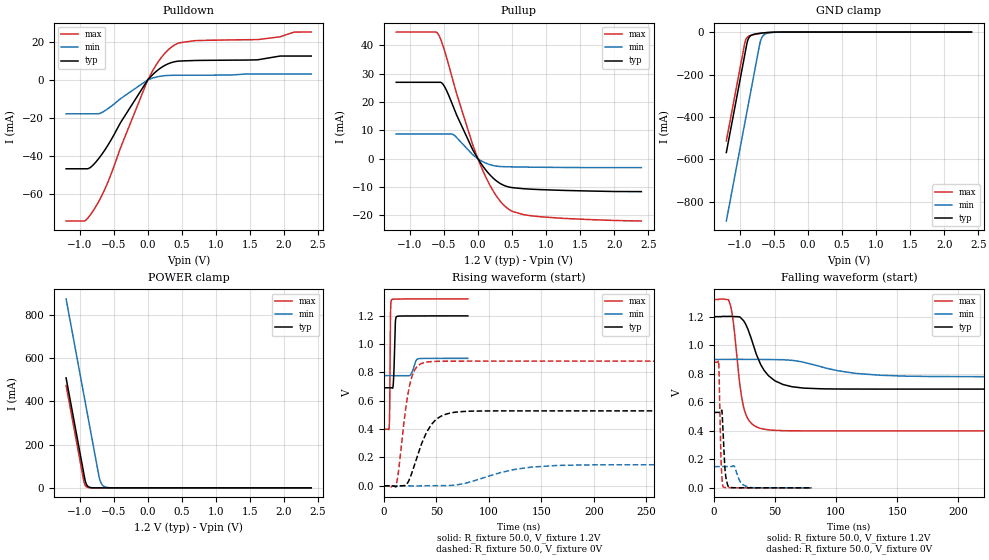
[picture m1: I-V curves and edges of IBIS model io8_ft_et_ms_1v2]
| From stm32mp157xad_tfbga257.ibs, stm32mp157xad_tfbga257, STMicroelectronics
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[Model]   io8_ft_et_ms_1v2
Model_type I/O
Polarity   Non-Inverting
Enable   Active-Low
| CAP_THRESHOLD on pad IOFT is "UDTCAPC" :
| Rising=20.00f vddiom   Falling=80.00f vddiom
| C_comp min and max val. don't necessarily correlate with the min and max pvt
| but are the smallest and greatest pad capacitance found.
| var   typ   min   max
C_comp   3.10945pF  3.08865pF  3.12940pF
|C_comp_pullup   1.82110pF  1.58845pF  1.75300pF
|C_comp_pulldown   1.28835pF  1.50020pF  1.37640pF
Vinl = 360.0mV
Vinh = 792.0mV
Vmeas = 600.0mV   | Reference voltage for timing measurements
Cref  = 50.0pF   | Timing specification test load capacitance value
Rref  = 100.0MOhm   | Timing specification test load resistance value
Vref  = 0V   | Timing specification test load voltage
[Model Spec]
| TIME_THRESHOLD on pin ZIV11 is "CMOS" :
| Rising=40.00f vdd   Falling=60.00f vdd
Vinl 463.60000mV 362.60000mV 506.60000mV
Vinh 741.40000mV 545.40000mV 817.40000mV
| variable   typ   min   max
[Temperature Range] 25.0 140.0 -40.0
| variable   typ   min   max
[Voltage Range] 1.2V 900.0mV 1.32V
| variable   typ   min   max
[POWER Clamp Reference] 1.2V 900.0mV 1.32V
| variable   typ   min   max
[GND Clamp Reference] 0V 0V 0V
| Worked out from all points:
|   slope of the pulldown table from 0 to 0.18 V, typ, clamps not added: 30 ohm
|   slope of the pullup table from 0 to 0.18 V, typ, clamps not added: 31.1 ohm
|   GND clamp passes 1 mA (typ) near -0.52 V on its own axis
|   POWER clamp passes 1 mA (typ) near -0.83 V on its own axis
|   rising waveform, R_fixture 50.0, V_fixture 1.2V: 20-80 % time 1.12ns typ, 3.33ns min, 572ps max; typ from 0.692 V to 1.2 V
|   falling waveform, R_fixture 50.0, V_fixture 1.2V: 20-80 % time 15.5ns typ, 40.7ns min, 7.6ns max; typ from 1.2 V to 0.692 V
|   rising waveform, R_fixture 50.0, V_fixture 0V: 20-80 % time 17.1ns typ, 44.6ns min, 9.23ns max; typ from 0 V to 0.529 V
|   falling waveform, R_fixture 50.0, V_fixture 0V: 20-80 % time 2.03ns typ, 4.67ns min, 1.44ns max; typ from 0.529 V to 0 V
[POWER Clamp]
-1.2V     508.8mA    874.1mA    473.5mA
-940mV    66.83mA    432.1mA    31.5mA
-930mV    49.83mA    415.1mA    19.15mA
-910mV    22.88mA    381.1mA    7.077mA
-880mV    7.117mA    330.1mA    1.59mA
-830mV    1.017mA    245.1mA    132uA
-720mV    14.05uA    58.12mA    554nA
-690mV    4.373uA    25.03mA    124.8nA
-650mV    922.5nA    8.136mA    17.23nA
-600mV    132.6nA    1.998mA    1.565nA
-490mV    2.858nA    90.92uA    111.8pA
2.4V      0A         0A         0A
[GND Clamp]
-1.2V     -567.2mA   -889.7mA   -512.2mA
-930mV    -108.2mA   -430.7mA   -53.23mA
-920mV    -91.21mA   -413.7mA   -40.49mA
-890mV    -43.51mA   -362.7mA   -23.59mA
-860mV    -22.57mA   -311.7mA   -17.89mA
-810mV    -12.11mA   -226.7mA   -13.23mA
-710mV    -6.053mA   -57.05mA   -7.064mA
-680mV    -4.908mA   -27.37mA   -5.632mA
-640mV    -3.605mA   -11.51mA   -3.985mA
-560mV    -1.665mA   -3.218mA   -1.61mA
-360mV    -34.72uA   -209.4uA   -9.248uA
2.4V      3.415nA    1.206uA    162.7pA
| variable   typ   min   max
[Pullup Reference] 1.2V 900.0mV 1.32V
| variable   typ   min   max
[Pulldown Reference] 0V 0V 0V
[Pullup]
-1.2V     26.92mA    8.713mA    44.63mA
-620mV    26.92mA    8.713mA    44.63mA
-580mV    26.92mA    8.713mA    43.74mA
-500mV    25.78mA    8.713mA    38.84mA
-360mV    18.23mA    8.473mA    26.98mA
-80mV     3.323mA    1.49mA     5.159mA
10mV      -383.6uA   -162.4uA   -606.4uA
220mV     -6.756mA   -2.388mA   -11.2mA
430mV     -9.815mA   -2.848mA   -17.42mA
670mV     -10.58mA   -2.95mA    -19.72mA
900mV     -10.88mA   -3.014mA   -20.42mA
2.4V      -11.6mA    -3.141mA   -21.96mA
[Pulldown]
-1.2V     -46.7mA    -17.86mA   -74.13mA
-930mV    -46.7mA    -17.86mA   -74.13mA
-770mV    -43.45mA   -17.86mA   -66.94mA
-580mV    -33.98mA   -14.99mA   -53.18mA
0V        0A         -7pA       0A
170mV     5.742mA    1.791mA    10.3mA
340mV     8.972mA    2.348mA    16.97mA
460mV     9.857mA    2.399mA    19.42mA
690mV     10.15mA    2.431mA    20.56mA
1.61V     10.49mA    3.05mA     21.11mA
2.16V     12.49mA    3.05mA     25.09mA
2.4V      12.49mA    3.05mA     25.09mA
[Ramp]
dV/dt_r 317.41827mV/17.10377ns 89.23301mV/44.63158ns 528.12888mV/9.23167ns
dV/dt_f 304.67945mV/15.47689ns 73.17214mV/40.67867ns 552.41113mV/7.59992ns
R_load = 50.0
| Removed startup time: 0s 0s 0s  .
| Removed end time: 79.9ns.
[Rising Waveform]
R_fixture   = 50.0
V_fixture   = 1.2V
V_fixture_min = 900.0mV
V_fixture_max = 1.32V
0s        692.2mV    778mV      399.3mV
5ns       692.2mV    778mV      414.8mV
5.5ns     692.2mV    778mV      557.6mV
6.3ns     692.3mV    778mV      1.238V
7.2ns     691.8mV    778mV      1.312V
8.9ns     720.8mV    778mV      1.318V
10.8ns    1.15V      778mV      1.318V
12ns      1.194V     778mV      1.319V
32.5ns    1.2V       896.6mV    1.32V
79.9ns    1.2V       899.8mV    1.32V
| Removed startup time: 0s 0s 0s  .
| Removed end time: 799.9ns.
[Falling Waveform]
R_fixture   = 50.0
V_fixture   = 1.2V
V_fixture_min = 900.0mV
V_fixture_max = 1.32V
0s        1.2V       900mV      1.32V
13.6ns    1.202V     900mV      1.274V
16.3ns    1.2V       900.3mV    1.123V
22.3ns    1.189V     900.6mV    648.3mV
26.5ns    1.136V     900.4mV    505mV
37.9ns    868.2mV    900.3mV    417.1mV
45.8ns    777.6mV    900mV      405.2mV
73.6ns    699mV      879.6mV    399.4mV
156.9ns   692.2mV    783.1mV    399.3mV
799.9ns   692.2mV    778mV      399.3mV
| Removed startup time: 0s 0s 0s  .
| Removed end time: 799.9ns.
[Rising Waveform]
R_fixture   = 50.0
V_fixture   = 0V
V_fixture_min = 0V
V_fixture_max = 0V
0s        720.8nV    1.004uV    -324.7nV
11.9ns    -4.079mV   1.104uV    14.48mV
20.8ns    4.614mV    24.65uV    550.1mV
25.3ns    64.55mV    -656.4uV   736.8mV
31.4ns    200.8mV    -1.891mV   840.2mV
40.9ns    381.3mV    -67.88uV   873.7mV
56.3ns    498.1mV    637.2uV    879.6mV
83ns      527mV      28.84mV    880.1mV
165.5ns   528.9mV    143.6mV    880.2mV
799.9ns   529mV      148.7mV    880.2mV
| Removed startup time: 0s 0s 0s  .
| Removed end time: 79.9ns.
[Falling Waveform]
R_fixture   = 50.0
V_fixture   = 0V
V_fixture_min = 0V
V_fixture_max = 0V
0s        529mV      148.8mV    880.2mV
3.8ns     529mV      148.8mV    882.5mV
5.7ns     531.6mV    148.8mV    192mV
6.5ns     532.8mV    148.8mV    67.23mV
7.5ns     363mV      148.8mV    6.791mV
9.3ns     98.32mV    148.8mV    2.112mV
12.1ns    3.711mV    148.8mV    1.417mV
16.5ns    769.9uV    152mV      777uV
28.4ns    463.3uV    4.727mV    116.4uV
79.9ns    2.53uV     133.1uV    -1.894uV
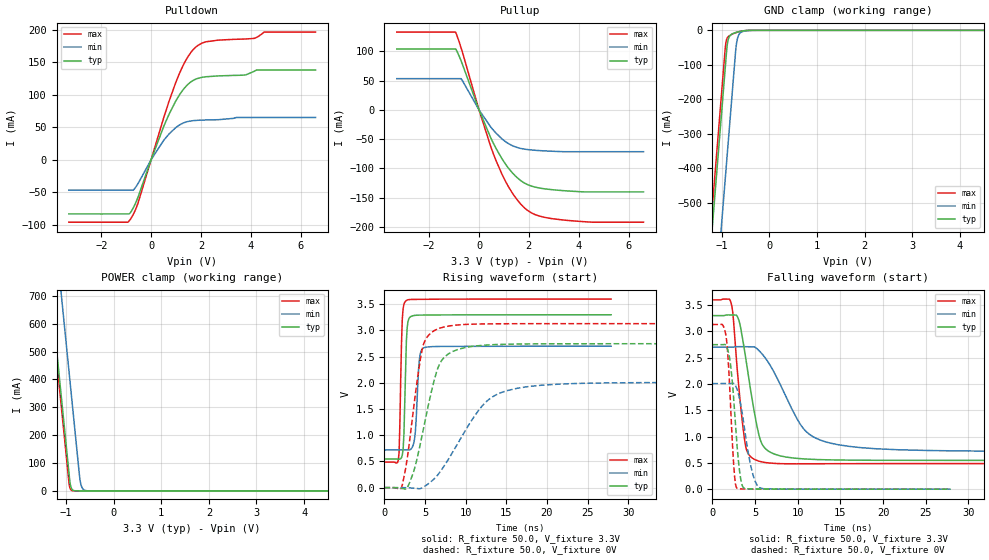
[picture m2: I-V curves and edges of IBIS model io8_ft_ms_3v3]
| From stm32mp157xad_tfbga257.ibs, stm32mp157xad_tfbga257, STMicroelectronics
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[Model]   io8_ft_ms_3v3
Model_type I/O
Polarity   Non-Inverting
Enable   Active-Low
| CAP_THRESHOLD on pad IOFT is "UDTCAPC" :
| Rising=20.00f vddiom   Falling=80.00f vddiom
| C_comp min and max val. don't necessarily correlate with the min and max pvt
| but are the smallest and greatest pad capacitance found.
| var   typ   min   max
C_comp   3.69202pF  3.65664pF  3.71215pF
|C_comp_pullup   2.23630pF  2.30075pF  2.13670pF
|C_comp_pulldown   1.45572pF  1.35589pF  1.57545pF
Vinl = 1.08V
Vinh = 2.16V
Vmeas = 1.65V   | Reference voltage for timing measurements
Cref  = 50.0pF   | Timing specification test load capacitance value
Rref  = 100.0MOhm   | Timing specification test load resistance value
Vref  = 0V   | Timing specification test load voltage
[Model Spec]
| TIME_THRESHOLD on pin ZIV11 is "CMOS" :
| Rising=40.00f vdd   Falling=60.00f vdd
Vinl 1.36060V 1.12960V 1.47360V
Vinh 1.71540V 1.45040V 1.82940V
| variable   typ   min   max
[Temperature Range] 25.0 140.0 -40.0
| variable   typ   min   max
[Voltage Range] 3.3V 2.7V 3.6V
| variable   typ   min   max
[POWER Clamp Reference] 3.3V 2.7V 3.6V
| variable   typ   min   max
[GND Clamp Reference] 0V 0V 0V
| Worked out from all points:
|   slope of the pulldown table from 0 to 0.495 V, typ, clamps not added: 9.86 ohm
|   slope of the pullup table from 0 to 0.495 V, typ, clamps not added: 9.93 ohm
|   GND clamp passes 1 mA (typ) near -0.52 V on its own axis
|   POWER clamp passes 1 mA (typ) near -0.83 V on its own axis
|   rising waveform, R_fixture 50.0, V_fixture 3.3V: 20-80 % time 280ps typ, 398ps min, 267ps max; typ from 0.547 V to 3.3 V
|   falling waveform, R_fixture 50.0, V_fixture 3.3V: 20-80 % time 1.7ns typ, 3.92ns min, 1.05ns max; typ from 3.3 V to 0.547 V
|   rising waveform, R_fixture 50.0, V_fixture 0V: 20-80 % time 2.38ns typ, 5.01ns min, 1.61ns max; typ from 0 V to 2.75 V
|   falling waveform, R_fixture 50.0, V_fixture 0V: 20-80 % time 808ps typ, 1.24ns min, 608ps max; typ from 2.75 V to 0 V
[POWER Clamp]
-3.3V     4.079A     4.444A     4.043A
-1.46V    950.8mA    1.316A     915.5mA
-1.28V    644.8mA    1.01A      609.5mA
-1.1V     338.8mA    704.1mA    303.5mA
-1.09V    321.8mA    687.1mA    286.5mA
-940mV    66.83mA    432.1mA    31.5mA
-910mV    22.88mA    381.1mA    7.077mA
-880mV    7.117mA    330.1mA    1.59mA
-710mV    9.523uA    43.89mA    337nA
-670mV    2.009uA    14.27mA    46.35nA
-590mV    90.76nA    1.508mA    1.088nA
6.6V      0A         0A         0A
[GND Clamp]
-3.3V     -4.139A    -4.461A    -4.081A
-1.26V    -670.8mA   -992.8mA   -613.3mA
-1.1V     -398.8mA   -720.8mA   -341.3mA
-930mV    -109.8mA   -431.8mA   -52.32mA
-890mV    -44.91mA   -363.8mA   -23.04mA
-870mV    -28.43mA   -329.8mA   -18.86mA
-760mV    -8.879mA   -142.8mA   -9.749mA
-710mV    -6.383mA   -58.04mA   -7.036mA
-670mV    -4.798mA   -22.41mA   -5.193mA
-610mV    -2.902mA   -7.057mA   -2.962mA
-500mV    -778.4uA   -1.643mA   -611.3uA
6.6V      9.179nA    3.066uA    465pA
| variable   typ   min   max
[Pullup Reference] 3.3V 2.7V 3.6V
| variable   typ   min   max
[Pulldown Reference] 0V 0V 0V
[Pullup]
-3.3V     103.9mA    53.38mA    132.9mA
-940mV    103.9mA    53.38mA    132.9mA
-720mV    83.88mA    53.38mA    106mA
0V        11.24pA    1.438nA    7.78pA
470mV     -47.62mA   -29.16mA   -62.69mA
690mV     -66.37mA   -40.04mA   -87.36mA
1.03V     -90.57mA   -53.18mA   -119.3mA
1.34V     -107.6mA   -61.16mA   -142.2mA
1.95V     -127.7mA   -67.75mA   -171.7mA
2.43V     -133.5mA   -69.51mA   -181.5mA
3.39V     -138mA     -71.4mA    -188.1mA
6.6V      -140.1mA   -71.44mA   -191.8mA
[Pulldown]
-3.3V     -83.56mA   -46.9mA    -96.31mA
-850mV    -82.46mA   -46.9mA    -92.78mA
-710mV    -73.83mA   -46.68mA   -83.86mA
-520mV    -57.22mA   -36.51mA   -66.23mA
0V        30fA       0A         200fA
720mV     70.07mA    39.69mA    90.11mA
1.29V     108.2mA    56.55mA    145.7mA
1.84V     125mA      60.7mA     175.1mA
2.21V     127.9mA    61.3mA     181.9mA
4.13V     136.2mA    65.14mA    187.1mA
4.54V     138.3mA    65.14mA    196.8mA
6.6V      138.3mA    65.14mA    196.8mA
[Ramp]
dV/dt_r 1.64845V/2.38267ns 1.20455V/5.00825ns 1.87844V/1.60905ns
dV/dt_f 1.65161V/1.69953ns 1.18897V/3.915ns 1.86819V/1.05154ns
R_load = 50.0
| Removed startup time: 0s 0s 0s  .
| Removed end time: 27.9ns.
[Rising Waveform]
R_fixture   = 50.0
V_fixture   = 3.3V
V_fixture_min = 2.7V
V_fixture_max = 3.6V
0s        547.3mV    718.4mV    486.3mV
1.7ns     545.4mV    718.4mV    521.9mV
1.8ns     543.4mV    718.4mV    669.2mV
2.2ns     624.6mV    718.4mV    3.229V
2.4ns     1.033V     718.5mV    3.503V
2.7ns     2.8V       717.9mV    3.573V
3.7ns     3.288V     925.2mV    3.594V
4.3ns     3.294V     2.444V     3.596V
4.8ns     3.294V     2.665V     3.596V
27.9ns    3.3V       2.7V       3.6V
| Removed startup time: 0s 0s 0s  .
| Removed end time: 59.9ns.
[Falling Waveform]
R_fixture   = 50.0
V_fixture   = 3.3V
V_fixture_min = 2.7V
V_fixture_max = 3.6V
0s        3.3V       2.7V       3.6V
2.2ns     3.313V     2.699V     3.537V
2.4ns     3.312V     2.701V     3.348V
3ns       3.259V     2.71V      2.12V
4ns       2.395V     2.708V     750.9mV
5.4ns     1.068V     2.645V     534.7mV
6.8ns     700.9mV    2.349V     495.6mV
10.6ns    576mV      1.167V     481.9mV
14.1ns    556.1mV    865.9mV    484.5mV
59.9ns    547.3mV    718.4mV    486.3mV
| Removed startup time: 0s 0s 0s  .
| Removed end time: 59.9ns.
[Rising Waveform]
R_fixture   = 50.0
V_fixture   = 0V
V_fixture_min = 0V
V_fixture_max = 0V
0s        73.75nV    500.8nV    80.39nV
2.1ns     -14.42mV   -13.32uV   -133.2uV
3ns       60.91mV    -2.69mV    776.8mV
4ns       543.2mV    -18.04mV   2.014V
4.7ns     1.048V     996.5uV    2.677V
6.7ns     2.331V     270.3mV    3.038V
8.3ns     2.592V     652.8mV    3.094V
12.2ns    2.719V     1.589V     3.125V
16.2ns    2.741V     1.893V     3.13V
59.9ns    2.747V     2.008V     3.131V
| Removed startup time: 0s 0s 0s  .
| Removed end time: 27.9ns.
[Falling Waveform]
R_fixture   = 50.0
V_fixture   = 0V
V_fixture_min = 0V
V_fixture_max = 0V
0s        2.747V     2.008V     3.131V
1.2ns     2.747V     2.008V     3.125V
1.6ns     2.732V     2.008V     2.915V
2.1ns     2.411V     2.008V     1.697V
2.5ns     1.706V     2.011V     465.1mV
2.9ns     808.2mV    1.894V     15.14mV
3.6ns     37mV       1.335V     3.293mV
4.6ns     3.573mV    372.5mV    1.816mV
5.6ns     2.096mV    23.77mV    1.294mV
27.9ns    5.636uV    76.44uV    700.5nV
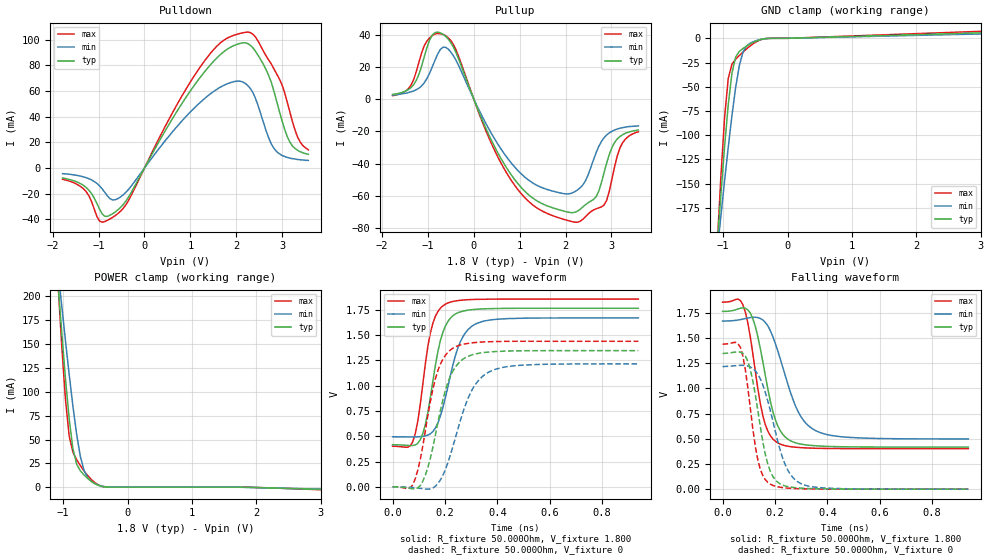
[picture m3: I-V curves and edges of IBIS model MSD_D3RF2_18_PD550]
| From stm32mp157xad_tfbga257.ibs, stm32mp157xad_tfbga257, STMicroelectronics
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[Model] MSD_D3RF2_18_PD550
Model_type   I/O
C_comp 2.402pF   2.319pF   2.523pF
Vinh = 1.150V
Vinl = 650.000mV
Vmeas = 900.000mV
Vref = 900.000mV
[Model Spec]
Vinh   1.150V   1.100V   1.200V
Vinl   650.000mV   600.000mV   700.000mV
Vmeas   900.000mV   850.000mV   950.000mV
Vref   900.000mV   850.000mV   950.000mV
[Temperature Range]   25.000   125.000   -40.000
[Voltage Range]   1.800V   1.700V   1.900V
[GND Clamp Reference]   0.00V   0.00V   0.00V
[Pulldown Reference]   0.00V   0.00V   0.00V
[POWER Clamp Reference]   1.800V   1.700V   1.900V
[Pullup Reference]   1.800V   1.700V   1.900V
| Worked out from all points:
|   slope of the pulldown table from 0 to 0.27 V, typ, clamps not added: 15.3 ohm
|   slope of the pullup table from 0 to 0.27 V, typ, clamps not added: 14.6 ohm
|   GND clamp passes 1 mA (typ) near -0.40 V on its own axis
|   POWER clamp passes 1 mA (typ) near -0.41 V on its own axis
|   rising waveform, R_fixture 50.000Ohm, V_fixture 1.800: 20-80 % time 57.6ps typ, 72.8ps min, 50ps max; typ from 0.417 V to 1.76 V
|   rising waveform, R_fixture 50.000Ohm, V_fixture 0: 20-80 % time 75.1ps typ, 94.6ps min, 66.2ps max; typ from 0.001 V to 1.35 V
|   falling waveform, R_fixture 50.000Ohm, V_fixture 1.800: 20-80 % time 65.7ps typ, 93.4ps min, 55.3ps max; typ from 1.76 V to 0.417 V
|   falling waveform, R_fixture 50.000Ohm, V_fixture 0: 20-80 % time 55.3ps typ, 77.6ps min, 46ps max; typ from 1.35 V to 0 V
[GND Clamp]
-1.785V   -902.5mA   -689.8mA   -1.211A
-1.094V   -215.2mA   -221.3mA   -216.1mA
-1.036V   -162.3mA   -184.1mA   -144mA
-978.8mV  -112.6mA   -147.7mA   -82.66mA
-921.2mV  -68.94mA   -112.7mA   -41.52mA
-863.6mV  -36.12mA   -79.94mA   -26.66mA
-806.1mV  -19.32mA   -50.9mA    -21.69mA
-748.5mV  -13.5mA    -28.05mA   -17.83mA
-690.9mV  -10.45mA   -14mA      -14.19mA
-575.8mV  -5.674mA   -4.868mA   -7.668mA
-287.9mV  -75.78uA   -126.4uA   -61.1uA
3.57V     6.676mA    5.321mA    8.541mA
[Power Clamp]
-1.77V    883.8mA    690.9mA    1.161A
-1.079V   213mA      227mA      212.9mA
-1.021V   161.4mA    189.7mA    147.4mA
-963.6mV  113.4mA    153.3mA    91.57mA
-906.1mV  71.59mA    118.1mA    53.46mA
-848.5mV  40.4mA     85.07mA    36.66mA
-790.9mV  24.12mA    55.69mA    28.9mA
-733.3mV  17.24mA    32.45mA    22.67mA
-618.2mV  9.128mA    9.881mA    12.16mA
-503mV    3.505mA    3.595mA    4.563mA
-272.7mV  30uA       102.8uA    29.36uA
3.585V    -3.38mA    -2.872mA   -4.063mA
[Pulldown]
-1.785V   -7.8mA     -4.4mA     -8.8mA
-1.267V   -15.3mA    -7.6mA     -18.6mA
-978.8mV  -32.1mA    -13.9mA    -41.38mA
-575.8mV  -32.5mA    -23.75mA   -35.4mA
1.267V    73.04mA    52.77mA    81.36mA
1.727V    90.57mA    64.39mA    99.46mA
2.245V    96.99mA    64.45mA    105.9mA
2.591V    80.73mA    35.6mA     91.06mA
2.821V    59.8mA     15.3mA     77.15mA
3.167V    20.2mA     7.7mA      43.7mA
3.339V    13.7mA     6.6mA      23.8mA
3.57V     10.7mA     5.9mA      14.1mA
[Pullup]
-1.77V    2.9mA      2.474mA    2.153mA
-1.367V   7.2mA      4.568mA    8.716mA
-1.136V   20.5mA     8.205mA    28.69mA
-906.1mV  39.64mA    19.85mA    39.36mA
-618.2mV  38.98mA    32.14mA    39.33mA
878.8mV   -49.38mA   -41.65mA   -52.88mA
1.455V    -64.24mA   -54.44mA   -68.75mA
2.203V    -70.07mA   -57.3mA    -76.21mA
2.664V    -60.5mA    -33.26mA   -67.94mA
2.836V    -45.7mA    -23.98mA   -65.61mA
3.182V    -23.2mA    -18.03mA   -30.38mA
3.585V    -19.1mA    -16.55mA   -20.22mA
[Ramp]
R_load=50.000Ohm
dV/dt_r   807.900mV/66.000ps  715.919mV/84.500ps  867.510mV/59.000ps
dV/dt_f   807.900mV/61.000ps  715.919mV/86.500ps  867.510mV/51.500ps
[Rising waveform]
R_fixture=50.000Ohm
V_fixture=1.800
V_fixture_min=1.700
V_fixture_max=1.900
0s        416.6mV    495.1mV    401.7mV
68ps      408.3mV    493.3mV    406.1mV
87ps      414.5mV    493.9mV    529.6mV
106ps     467.1mV    496.4mV    820.3mV
144ps     878.6mV    523.7mV    1.517V
173ps     1.337V     631mV      1.732V
202ps     1.59V      886.1mV    1.805V
259ps     1.729V     1.435V     1.843V
326ps     1.755V     1.619V     1.852V
938ps     1.764V     1.669V     1.855V
[Rising waveform]
R_fixture=50.000Ohm
V_fixture=0
0s        1.095mV    971.2uV    968.1uV
77ps      -18.76mV   -6.678mV   20.19mV
115ps     53.9mV     -18.24mV   397mV
144ps     279.7mV    -20.14mV   840.8mV
173ps     635.8mV    32.55mV    1.149V
202ps     957.7mV    174.2mV    1.301V
230ps     1.143V     396.9mV    1.369V
298ps     1.299V     931.5mV    1.421V
374ps     1.333V     1.142V     1.434V
938ps     1.346V     1.215V     1.438V
[Falling waveform]
R_fixture=50.000Ohm
V_fixture=1.800
V_fixture_min=1.700
V_fixture_max=1.900
0s        1.763V     1.667V     1.854V
68ps      1.794V     1.681V     1.871V
87ps      1.794V     1.692V     1.756V
106ps     1.746V     1.701V     1.508V
154ps     1.259V     1.677V     725.3mV
183ps     864.5mV    1.568V     527mV
211ps     626.1mV    1.369V     458.5mV
288ps     452.7mV    770.7mV    413.8mV
365ps     428.7mV    568.7mV    404.9mV
938ps     417.4mV    497.7mV    401.9mV
[Falling waveform]
R_fixture=50.000Ohm
V_fixture=0
0s        1.346V     1.216V     1.438V
68ps      1.359V     1.228V     1.405V
96ps      1.271V     1.221V     1.015V
115ps     1.08V      1.198V     609.3mV
135ps     773.5mV    1.138V     284.1mV
163ps     345.6mV    961.2mV    94.59mV
183ps     171.9mV    771.9mV    48.4mV
240ps     31.02mV    237mV      12.56mV
307ps     9.365mV    46.4mV     3.425mV
938ps     2.27uV     29.69uV    2.355uV
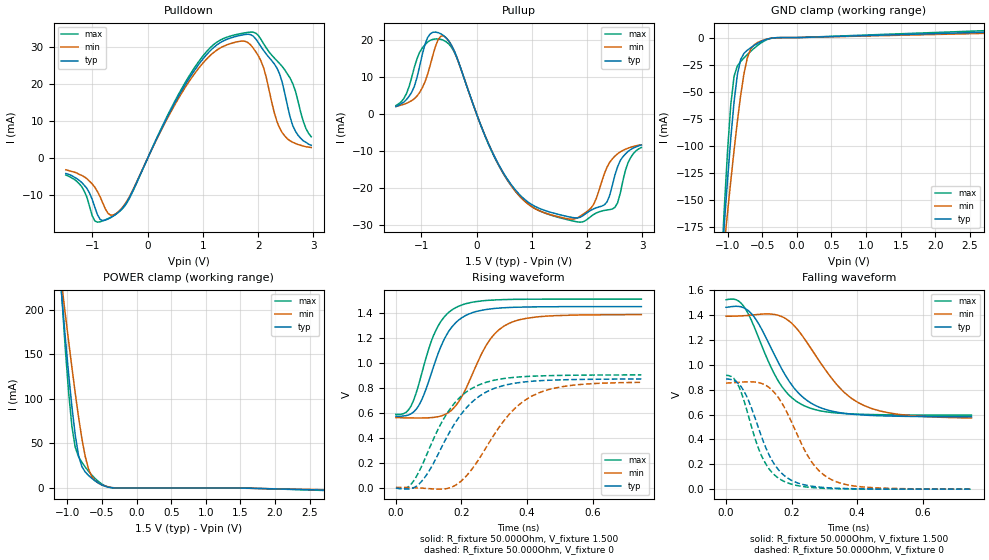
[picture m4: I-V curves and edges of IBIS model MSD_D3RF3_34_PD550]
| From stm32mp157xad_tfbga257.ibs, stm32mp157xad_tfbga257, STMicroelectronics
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[Model] MSD_D3RF3_34_PD550
Model_type   I/O
C_comp 2.415pF   2.332pF   2.538pF
Vinh = 925.000mV
Vinl = 575.000mV
Vmeas = 750.000mV
Vref = 750.000mV
[Model Spec]
Vinh   925.000mV   888.000mV   963.000mV
Vinl   575.000mV   538.000mV   613.000mV
Vmeas   750.000mV   713.000mV   788.000mV
Vref   750.000mV   713.000mV   788.000mV
[Temperature Range]   25.000   125.000   -40.000
[Voltage Range]   1.500V   1.425V   1.575V
[GND Clamp Reference]   0.00V   0.00V   0.00V
[Pulldown Reference]   0.00V   0.00V   0.00V
[POWER Clamp Reference]   1.500V   1.425V   1.575V
[Pullup Reference]   1.500V   1.425V   1.575V
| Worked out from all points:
|   slope of the pulldown table from 0 to 0.225 V, typ, clamps not added: 31.5 ohm
|   slope of the pullup table from 0 to 0.225 V, typ, clamps not added: 26.9 ohm
|   GND clamp passes 1 mA (typ) near -0.40 V on its own axis
|   POWER clamp passes 1 mA (typ) near -0.41 V on its own axis
|   rising waveform, R_fixture 50.000Ohm, V_fixture 1.500: 20-80 % time 81.2ps typ, 97.5ps min, 72.6ps max; typ from 0.573 V to 1.46 V
|   rising waveform, R_fixture 50.000Ohm, V_fixture 0: 20-80 % time 127ps typ, 143ps min, 115ps max; typ from -0.005 V to 0.873 V
|   falling waveform, R_fixture 50.000Ohm, V_fixture 1.500: 20-80 % time 118ps typ, 146ps min, 103ps max; typ from 1.46 V to 0.582 V
|   falling waveform, R_fixture 50.000Ohm, V_fixture 0: 20-80 % time 84.6ps typ, 103ps min, 73.9ps max; typ from 0.885 V to 0 V
[GND Clamp]
-1.48V    -594.8mA   -480.6mA   -764.4mA
-1.098V   -218.9mA   -223.9mA   -221.1mA
-1.05V    -174.6mA   -192.8mA   -160.4mA
-1.002V   -132.4mA   -162.4mA   -105.9mA
-954.6mV  -93.31mA   -132.8mA   -62.14mA
-906.8mV  -59.46mA   -104.2mA   -35.71mA
-859.1mV  -34.19mA   -77.49mA   -26.14mA
-811.4mV  -20.25mA   -53.36mA   -22.06mA
-715.9mV  -11.67mA   -18.95mA   -15.74mA
-572.7mV  -5.563mA   -4.762mA   -7.514mA
-286.4mV  -72.83uA   -122.9uA   -58.2uA
2.959V    5.427mA    4.273mA    6.977mA
[Power Clamp]
-1.459V   578.6mA    479.9mA    724.1mA
-1.077V   211.6mA    226mA      211mA
-1.03V    168.7mA    195.1mA    156.2mA
-981.8mV  128mA      164.7mA    107.3mA
-934.1mV  90.94mA    135mA      68.85mA
-886.4mV  59.42mA    106.5mA    45.71mA
-838.6mV  36.53mA    79.7mA     35.09mA
-743.2mV  18.14mA    35.77mA    23.67mA
-647.7mV  10.94mA    13mA       14.59mA
-552.3mV  5.6mA      5.535mA    7.379mA
-313.6mV  101uA      237.7uA    117.6uA
2.98V     -2.761mA   -2.315mA   -3.352mA
[Pulldown]
-1.48V    -4.1mA     -3.1mA     -4.5mA
-1.193V   -6.5mA     -4.6mA     -7.6mA
-954.6mV  -13.21mA   -7.8mA     -16.88mA
-811.4mV  -16.78mA   -12.04mA   -16.85mA
-572.7mV  -15.07mA   -14.9mA    -15.03mA
-334.1mV  -10.72mA   -10.48mA   -10.95mA
906.8mV   24.93mA    23.93mA    25.67mA
1.766V    33.35mA    31.49mA    33.79mA
2.052V    30.02mA    26.15mA    31.97mA
2.434V    20.49mA    6.9mA      24.73mA
2.625V    8.8mA      4.3mA      20.1mA
2.959V    3.5mA      2.9mA      5.8mA
[Pullup]
-1.459V   2mA        2.014mA    2.271mA
-1.173V   5.9mA      3.629mA    9.943mA
-886.4mV  20.67mA    10.7mA     19.45mA
-600mV    21.24mA    21.13mA    19.93mA
-409.1mV  17.29mA    17.18mA    16.91mA
593.2mV   -18.4mA    -18.64mA   -18.71mA
1.643V    -27.73mA   -28.34mA   -28.59mA
2.073V    -26mA      -25.39mA   -27.65mA
2.311V    -24.58mA   -16.14mA   -26.08mA
2.502V    -16.5mA    -11.4mA    -25.27mA
2.741V    -10.1mA    -9.229mA   -13.11mA
2.98V     -8.4mA     -8.343mA   -9.071mA
[Ramp]
R_load=50.000Ohm
dV/dt_r   524.370mV/105.000ps  502.199mV/121.500ps  548.130mV/94.500ps
dV/dt_f   524.370mV/102.000ps  502.199mV/126.000ps  548.130mV/89.000ps
[Rising waveform]
R_fixture=50.000Ohm
V_fixture=1.500
V_fixture_min=1.425
V_fixture_max=1.575
0s        573.4mV    562.2mV    588.4mV
39ps      583.9mV    560mV      626.5mV
69ps      656.3mV    559.1mV    823.3mV
123ps     1.036V     567.2mV    1.27V
154ps     1.225V     592.3mV    1.391V
192ps     1.348V     692mV      1.459V
276ps     1.432V     1.146V     1.505V
345ps     1.448V     1.32V      1.513V
460ps     1.454V     1.379V     1.516V
749ps     1.455V     1.391V     1.516V
[Rising waveform]
R_fixture=50.000Ohm
V_fixture=0
0s        -4.988mV   863.7uV    -5.147mV
39ps      -11.6mV    -713.4uV   7.723mV
77ps      45.06mV    -4.813mV   162.7mV
161ps     432.4mV    -4.387mV   616.2mV
199ps     589.6mV    51.34mV    734.3mV
253ps     731.7mV    227.1mV    825mV
345ps     830.2mV    586.9mV    882mV
414ps     854.6mV    734.9mV    895.2mV
529ps     867.8mV    819.4mV    902.8mV
749ps     873.1mV    846mV      905.7mV
[Falling waveform]
R_fixture=50.000Ohm
V_fixture=1.500
V_fixture_min=1.425
V_fixture_max=1.575
0s        1.462V     1.39V      1.522V
39ps      1.469V     1.392V     1.511V
77ps      1.412V     1.399V     1.359V
161ps     1.011V     1.396V     862.6mV
199ps     843.6mV    1.337V     739.2mV
238ps     731.4mV    1.213V     670.9mV
337ps     619.5mV    843.1mV    612.3mV
421ps     595.5mV    672.5mV    601.3mV
529ps     586.1mV    600.7mV    596.5mV
749ps     581.6mV    572.3mV    595mV
[Falling waveform]
R_fixture=50.000Ohm
V_fixture=0
0s        885.2mV    852.8mV    914.7mV
31ps      863.6mV    857.7mV    865.4mV
54ps      791.7mV    861.4mV    718.3mV
92ps      545.5mV    859.9mV    379.1mV
115ps     374.6mV    842.9mV    232mV
146ps     206mV      780.6mV    118.7mV
177ps     110.8mV    661.9mV    62.55mV
261ps     24.19mV    219.7mV    13.27mV
330ps     8.491mV    66.49mV    4.009mV
749ps     51.03uV    417uV      -15.77uV
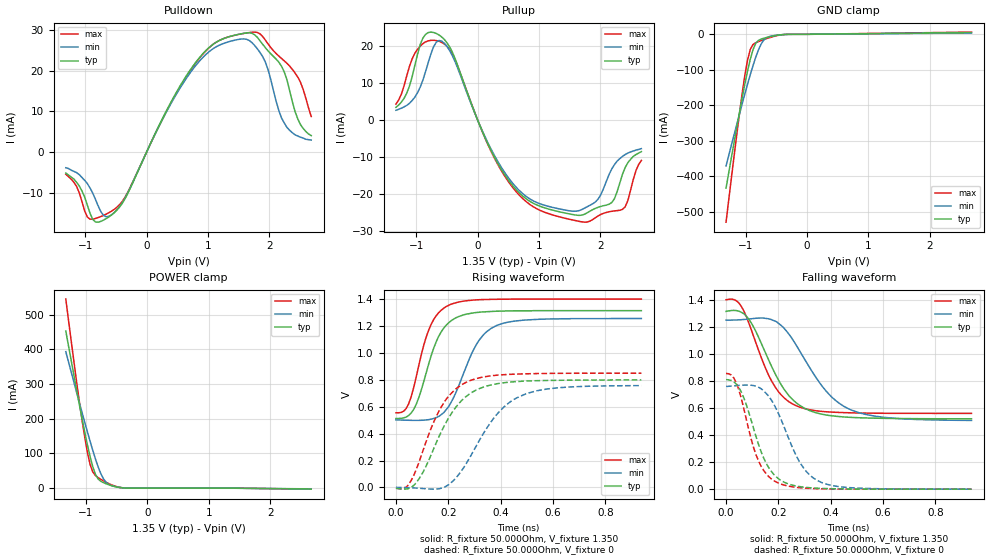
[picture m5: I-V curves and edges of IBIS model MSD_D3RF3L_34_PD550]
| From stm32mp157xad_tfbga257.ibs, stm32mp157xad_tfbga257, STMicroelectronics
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[Model] MSD_D3RF3L_34_PD550
Model_type   I/O
C_comp 2.422pF   2.338pF   2.546pF
Vinh = 810.000mV
Vinl = 540.000mV
Vmeas = 675.000mV
Vref = 675.000mV
[Model Spec]
Vinh   810.000mV   777.000mV   860.000mV
Vinl   540.000mV   507.000mV   590.000mV
Vmeas   675.000mV   642.000mV   725.000mV
Vref   675.000mV   642.000mV   725.000mV
[Temperature Range]   25.000   125.000   -40.000
[Voltage Range]   1.350V   1.283V   1.450V
[GND Clamp Reference]   0.00V   0.00V   0.00V
[Pulldown Reference]   0.00V   0.00V   0.00V
[POWER Clamp Reference]   1.350V   1.283V   1.450V
[Pullup Reference]   1.350V   1.283V   1.450V
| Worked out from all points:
|   slope of the pulldown table from 0 to 0.203 V, typ, clamps not added: 31 ohm
|   slope of the pullup table from 0 to 0.203 V, typ, clamps not added: 26.2 ohm
|   GND clamp passes 1 mA (typ) near -0.40 V on its own axis
|   POWER clamp passes 1 mA (typ) near -0.41 V on its own axis
|   rising waveform, R_fixture 50.000Ohm, V_fixture 1.350: 20-80 % time 83.9ps typ, 106ps min, 74.4ps max; typ from 0.511 V to 1.31 V
|   rising waveform, R_fixture 50.000Ohm, V_fixture 0: 20-80 % time 133ps typ, 157ps min, 118ps max; typ from -0.006 V to 0.797 V
|   falling waveform, R_fixture 50.000Ohm, V_fixture 1.350: 20-80 % time 130ps typ, 162ps min, 111ps max; typ from 1.32 V to 0.521 V
|   falling waveform, R_fixture 50.000Ohm, V_fixture 0: 20-80 % time 89.1ps typ, 110ps min, 77.3ps max; typ from 0.811 V to 0 V
[GND Clamp]
-1.318V   -433.7mA   -371mA     -529.9mA
-1.142V   -261.3mA   -253.3mA   -281.1mA
-1.055V   -178.8mA   -195.8mA   -166mA
-1.011V   -139.6mA   -167.6mA   -114.8mA
-966.7mV  -102.8mA   -140.2mA   -71.91mA
-922.7mV  -69.98mA   -113.5mA   -42.24mA
-878.8mV  -43.33mA   -88.28mA   -28.82mA
-834.9mV  -25.71mA   -64.84mA   -23.86mA
-790.9mV  -17.19mA   -44.16mA   -20.64mA
-703mV    -11.03mA   -16.2mA    -14.94mA
-527.3mV  -4.003mA   -3.392mA   -5.338mA
2.68V     4.841mA    3.764mA    6.269mA
[Power Clamp]
-1.33V    452.9mA    393.3mA    544.8mA
-1.111V   242.4mA    247.7mA    251.5mA
-1.023V   162.7mA    190.7mA    148.6mA
-978.8mV  125.6mA    162.7mA    104mA
-934.9mV  91.47mA    135.5mA    68.54mA
-890.9mV  62.09mA    109.1mA    46.9mA
-847mV    39.75mA    84.16mA    36.4mA
-803mV    26.39mA    61.34mA    30.3mA
-715.1mV  15.71mA    26.57mA    20.81mA
-671.2mV  12.48mA    16.48mA    16.64mA
-407.6mV  908uA      1.189mA    1.109mA
2.668V    -2.431mA   -2.026mA   -2.89mA
[Pulldown]
-1.318V   -5.2mA     -3.9mA     -5.5mA
-966.7mV  -13.1mA    -7.8mA     -16.02mA
-834.9mV  -17.24mA   -11.67mA   -16.38mA
-571.2mV  -15.5mA    -15.46mA   -14.57mA
-351.5mV  -11.49mA   -11.32mA   -11.11mA
747mV     20.94mA    20.23mA    20.79mA
1.098V    26.63mA    25.52mA    26.63mA
1.582V    29.15mA    27.77mA    29.12mA
1.933V    25.61mA    22.08mA    27.47mA
2.197V    21.04mA    8.3mA      22.95mA
2.461V    8.1mA      3.9mA      18.4mA
2.68V     4mA        2.9mA      8.7mA
[Pullup]
-1.33V    3.4mA      2.605mA    4.252mA
-1.155V   7.2mA      3.91mA     11.86mA
-978.8mV  17.7mA     7.335mA    19.11mA
-715.1mV  23.66mA    19.86mA    21.56mA
-495.5mV  20.82mA    19.82mA    19.88mA
251.5mV   -9.373mA   -8.925mA   -9.6mA
866.7mV   -22.22mA   -21.56mA   -23.09mA
1.702V    -25.8mA    -24.26mA   -27.63mA
1.965V    -23.66mA   -21.42mA   -26.01mA
2.185V    -22.41mA   -13.33mA   -24.76mA
2.361V    -14.7mA    -9.885mA   -24.24mA
2.668V    -8.6mA     -7.795mA   -10.98mA
[Ramp]
R_load=50.000Ohm
dV/dt_r   476.220mV/109.000ps  450.749mV/132.000ps  505.050mV/96.500ps
dV/dt_f   476.220mV/109.500ps  450.749mV/137.000ps  505.050mV/94.000ps
[Rising waveform]
R_fixture=50.000Ohm
V_fixture=1.350
V_fixture_min=1.283
V_fixture_max=1.450
0s        511.3mV    501.2mV    553.6mV
39ps      522.1mV    498.8mV    585mV
68ps      579.1mV    497.6mV    741.4mV
125ps     914.3mV    502.8mV    1.166V
163ps     1.119V     525.9mV    1.295V
202ps     1.222V     601.1mV    1.351V
307ps     1.297V     1.058V     1.391V
384ps     1.307V     1.2V       1.395V
556ps     1.311V     1.248V     1.397V
938ps     1.311V     1.253V     1.397V
[Rising waveform]
R_fixture=50.000Ohm
V_fixture=0
0s        -6.201mV   740.2uV    -5.494mV
39ps      -11.78mV   -776.2uV   1.56mV
77ps      33.81mV    -4.35mV    130.3mV
173ps     411.8mV    -5.413mV   596mV
221ps     574.6mV    53.05mV    716.6mV
269ps     675.6mV    178.1mV    780.3mV
374ps     764.9mV    514.4mV    830.1mV
489ps     788.3mV    688mV      842.4mV
623ps     794.7mV    739.6mV    846.4mV
938ps     797.3mV    755.3mV    847.3mV
[Falling waveform]
R_fixture=50.000Ohm
V_fixture=1.350
V_fixture_min=1.283
V_fixture_max=1.450
0s        1.317V     1.252V     1.403V
48ps      1.319V     1.254V     1.381V
87ps      1.259V     1.26V      1.231V
173ps     913.7mV    1.256V     805.1mV
221ps     742.3mV    1.194V     678.1mV
269ps     638.4mV    1.064V     617.4mV
384ps     549mV      722.9mV    573.1mV
470ps     532.5mV    593.5mV    565.9mV
633ps     523.8mV    526.6mV    561.8mV
938ps     521.2mV    509.1mV    561.2mV
[Falling waveform]
R_fixture=50.000Ohm
V_fixture=0
0s        811mV      760.5mV    856.7mV
39ps      778.2mV    766.6mV    789mV
68ps      676.3mV    770.7mV    596.1mV
96ps      510.6mV    769.8mV    370.3mV
125ps     326.3mV    754.3mV    204.9mV
154ps     189.8mV    707.5mV    111.7mV
192ps     91.2mV     594.1mV    52.63mV
288ps     17.19mV    180.4mV    9.588mV
365ps     5.745mV    49.69mV    2.615mV
938ps     9.235uV    88.41uV    6.922uV
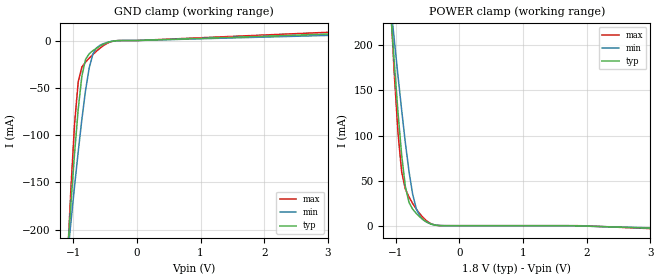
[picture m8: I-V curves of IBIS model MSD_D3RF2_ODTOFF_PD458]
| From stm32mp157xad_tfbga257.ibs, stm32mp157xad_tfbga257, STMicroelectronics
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[Model] MSD_D3RF2_ODTOFF_PD458
Model_type   Input
C_comp 2.372pF   2.291pF   2.493pF
Vinh = 1.150V
Vinl = 650.000mV
[Temperature Range]   25.000   125.000   -40.000
[Voltage Range]   1.800V   1.700V   1.900V
[GND Clamp Reference]   0.00V   0.00V   0.00V
[POWER Clamp Reference]   1.800V   1.700V   1.900V
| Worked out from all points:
|   GND clamp passes 1 mA (typ) near -0.40 V on its own axis
|   POWER clamp passes 1 mA (typ) near -0.41 V on its own axis
[GND Clamp]
-1.785V   -963.8mA   -721.4mA   -1.334A
-1.094V   -230mA     -231.7mA   -237.3mA
-1.036V   -173.1mA   -192.6mA   -157mA
-978.8mV  -119.7mA   -154.4mA   -88.6mA
-921.2mV  -72.66mA   -117.7mA   -43.78mA
-863.6mV  -37.62mA   -83.31mA   -28.09mA
-806.1mV  -19.99mA   -52.84mA   -22.81mA
-748.5mV  -13.96mA   -28.93mA   -18.7mA
-690.9mV  -10.77mA   -14.34mA   -14.84mA
-575.8mV  -5.799mA   -4.937mA   -7.938mA
-287.9mV  -74.38uA   -124.7uA   -59.7uA
3.57V     8.072mA    6.421mA    10.35mA
[Power Clamp]
-1.77V    980.5mA    743.7mA    1.344A
-1.079V   237.9mA    245.5mA    244.3mA
-1.021V   179.8mA    205.5mA    167.2mA
-963.6mV  125.4mA    166.2mA    102.9mA
-906.1mV  78.21mA    128.1mA    59.72mA
-848.5mV  43.54mA    92.2mA     40.73mA
-790.9mV  25.78mA    60.14mA    31.81mA
-733.3mV  18.32mA    34.79mA    24.69mA
-618.2mV  9.53mA     10.31mA    12.95mA
-503mV    3.583mA    3.662mA    4.727mA
-272.7mV  29uA       99.42uA    29.36uA
3.585V    -4.088mA   -3.468mA   -4.924mA
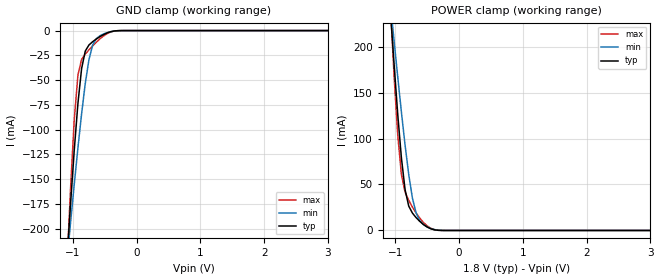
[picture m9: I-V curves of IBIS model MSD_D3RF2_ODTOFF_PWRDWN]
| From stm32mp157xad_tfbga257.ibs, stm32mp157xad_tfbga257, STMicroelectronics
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[Model] MSD_D3RF2_ODTOFF_PWRDWN
Model_type   Input
C_comp 2.550pF   2.465pF   2.675pF
Vinh = 1.150V
Vinl = 650.000mV
[Model Spec]
Vinh   1.150V   1.100V   1.200V
Vinl   650.000mV   600.000mV   700.000mV
[Temperature Range]   25.000   125.000   -40.000
[Voltage Range]   1.800V   1.700V   1.900V
[GND Clamp Reference]   0.00V   0.00V   0.00V
[POWER Clamp Reference]   1.800V   1.700V   1.900V
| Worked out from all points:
|   GND clamp passes 1 mA (typ) near -0.40 V on its own axis
|   POWER clamp passes 1 mA (typ) near -0.40 V on its own axis
[GND Clamp]
-1.785V   -966.4mA   -723.7mA   -1.337A
-1.094V   -231.2mA   -232.7mA   -238.9mA
-1.036V   -174.3mA   -193.5mA   -158.4mA
-978.8mV  -120.7mA   -155.3mA   -89.93mA
-921.2mV  -73.57mA   -118.5mA   -44.97mA
-863.6mV  -38.42mA   -83.97mA   -29.14mA
-806.1mV  -20.7mA    -53.41mA   -23.73mA
-748.5mV  -14.55mA   -29.42mA   -19.49mA
-690.9mV  -11.27mA   -14.75mA   -15.5mA
-575.8mV  -6.108mA   -5.194mA   -8.348mA
-287.9mV  -82.98uA   -135.9uA   -69.31uA
3.57V     43.06nA    683.4nA    4.025nA
[Power Clamp]
-1.77V    983.3mA    746.2mA    1.347A
-1.079V   239.2mA    246.7mA    245.9mA
-1.021V   181mA      206.6mA    168.6mA
-963.6mV  126.5mA    167.2mA    104.2mA
-906.1mV  79.17mA    129mA      60.93mA
-848.5mV  44.38mA    92.93mA    41.79mA
-790.9mV  26.51mA    60.78mA    32.72mA
-733.3mV  18.93mA    35.34mA    25.46mA
-618.2mV  9.936mA    10.68mA    13.46mA
-503mV    3.795mA    3.875mA    4.994mA
-272.7mV  36.62uA    119uA      36.58uA
3.585V    -63.01nA   -1.1uA     -7.198nA
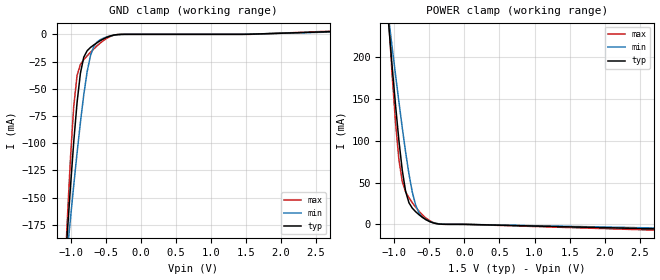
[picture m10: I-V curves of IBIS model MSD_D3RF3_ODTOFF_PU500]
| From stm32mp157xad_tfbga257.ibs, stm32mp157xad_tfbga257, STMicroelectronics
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[Model] MSD_D3RF3_ODTOFF_PU500
Model_type   Input
C_comp 2.404pF   2.323pF   2.527pF
Vinh = 925.000mV
Vinl = 575.000mV
[Temperature Range]   25.000   125.000   -40.000
[Voltage Range]   1.500V   1.425V   1.575V
[GND Clamp Reference]   0.00V   0.00V   0.00V
[POWER Clamp Reference]   1.500V   1.425V   1.575V
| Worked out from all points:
|   GND clamp passes 1 mA (typ) near -0.40 V on its own axis
|   POWER clamp passes 1 mA (typ) near -0.41 V on its own axis
[GND Clamp]
-1.48V    -635.7mA   -502.7mA   -842.7mA
-1.098V   -233.9mA   -234.3mA   -243mA
-1.05V    -186.4mA   -201.8mA   -175.4mA
-1.002V   -141mA     -169.9mA   -114.5mA
-954.6mV  -98.88mA   -138.8mA   -66.14mA
-906.8mV  -62.55mA   -108.8mA   -37.69mA
-859.1mV  -35.62mA   -80.76mA   -27.61mA
-811.4mV  -21mA      -55.44mA   -23.29mA
-715.9mV  -12.07mA   -19.49mA   -16.54mA
-572.7mV  -5.7mA     -4.832mA   -7.806mA
-286.4mV  -68.01uA   -115.6uA   -55.41uA
2.959V    2.961mA    2.521mA    3.579mA
[Power Clamp]
-1.459V   642.6mA    517mA      840.5mA
-1.077V   236.4mA    244.6mA    242.1mA
-1.03V    188.2mA    211.4mA    177.6mA
-981.8mV  142.2mA    178.7mA    121mA
-934.1mV  100.1mA    146.6mA    77.23mA
-886.4mV  64.71mA    115.6mA    51.11mA
-838.6mV  39.41mA    86.44mA    39.03mA
-743.2mV  19.37mA    38.5mA     25.91mA
-647.7mV  11.55mA    13.74mA    15.71mA
-552.3mV  5.823mA    5.738mA    7.792mA
-313.6mV  107.5uA    246.9uA    121.4uA
2.98V     -5.962mA   -4.801mA   -7.623mA
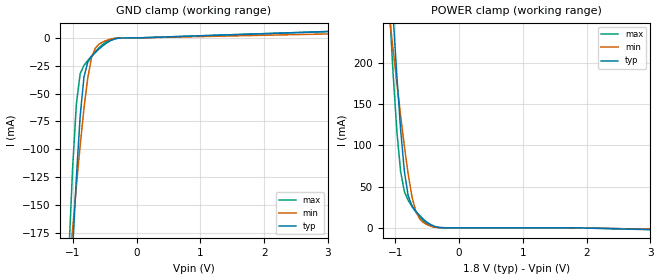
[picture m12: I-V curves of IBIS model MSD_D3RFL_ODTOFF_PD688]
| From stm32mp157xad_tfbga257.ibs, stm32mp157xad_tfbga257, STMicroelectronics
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[Model] MSD_D3RFL_ODTOFF_PD688
Model_type   Input
C_comp 2.409pF   2.347pF   2.556pF
Vinh = 1.440V
Vinl = 360.000mV
[Temperature Range]   25.000   125.000   -40.000
[Voltage Range]   1.800V   1.650V   1.950V
[GND Clamp Reference]   0.00V   0.00V   0.00V
[POWER Clamp Reference]   1.800V   1.650V   1.950V
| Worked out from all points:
|   GND clamp passes 1 mA (typ) near -0.34 V on its own axis
|   POWER clamp passes 1 mA (typ) near -0.35 V on its own axis
[GND Clamp]
-1.773V   -1.216A    -713.4mA   -1.315A
-1.064V   -264.6mA   -211.4mA   -194.5mA
-1.005V   -192mA     -171.7mA   -117.5mA
-945.5mV  -125.4mA   -133.2mA   -59.32mA
-886.4mV  -70.29mA   -96.76mA   -32.2mA
-827.3mV  -35.41mA   -63.67mA   -24.81mA
-768.2mV  -21.9mA    -36.34mA   -20.35mA
-709.1mV  -16.81mA   -18.04mA   -16.27mA
-650mV    -13.2mA    -9.277mA   -12.43mA
-531.8mV  -7.106mA   -3.617mA   -5.813mA
-236.4mV  -82.32uA   -40.33uA   -9.216uA
3.545V    6.707mA    4.232mA    6.861mA
[Power Clamp]
-1.745V   1.222A     726.7mA    1.305A
-1.095V   334.4mA    257.6mA    268.9mA
-1.036V   257.4mA    216.4mA    187.2mA
-977.3mV  184.3mA    175.9mA    117.4mA
-918.2mV  119.3mA    136.4mA    68.21mA
-859.1mV  68.46mA    98.96mA    43.87mA
-800mV    38.97mA    65.3mA     33.42mA
-740.9mV  26.99mA    38.17mA    25.87mA
-681.8mV  20.41mA    20.3mA     19.29mA
-563.6mV  10.6mA     6.448mA    8.735mA
-268.2mV  164uA      98.68uA    31.4uA
3.573V    -3.401mA   -2.347mA   -3.164mA
